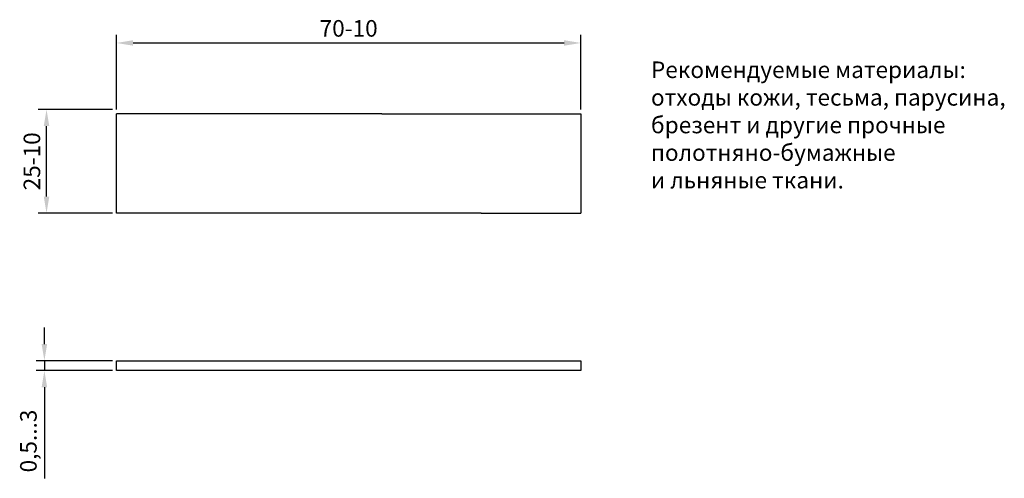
# Model space of a CAD drawing. Units: millimetres. Extents: x -73 to 75, y 113 to 182.
import ezdxf

# ---------------------------------------------------------------- set-up
doc = ezdxf.new("R2010")
doc.units = ezdxf.units.MM
doc.header["$LTSCALE"] = 0.2
doc.dimstyles.new('ISO-25', dxfattribs={"dimtxt": 2.5, "dimasz": 2.5, "dimexe": 1.25, "dimexo": 0.625, "dimtad": 1, "dimtxsty": 'Standard', "dimcen": 2.5, "dimadec": 0, "dimazin": 0, "dimtfac": 1, "dimtmove": 0, "dimatfit": 3, "dimfxl": 0, "dimarcsym": 0})

# ---------------------------------------------------------------- blocks, each defined once
blk = doc.blocks.new('*D1')
at = {"color": 0, "lineweight": -2, "ltscale": 0.25}
for p, q in [((-58.5, 168.78), (-58.5, 180.07)), ((11.5, 168.78), (11.5, 180.07)), ((-56, 178.82), (9, 178.82))]:
    blk.add_line(p, q, dxfattribs=at)
at = {"color": 0, "lineweight": 15, "ltscale": 0.25}
for points in [[(-56, 179.24), (-56, 178.41), (-58.5, 178.82)], [(9, 179.24), (9, 178.41), (11.5, 178.82)]]:
    blk.add_solid(points, dxfattribs=at)
at = {"layer": 'Defpoints', "color": 0, "lineweight": 15, "ltscale": 0.25}
for p in [(11.5, 178.82), (-58.5, 168.15), (11.5, 168.15)]:
    blk.add_point(p, dxfattribs=at)
at = {"color": 0, "lineweight": 15, "ltscale": 0.25, "insert": (-23.5, 180.7), "char_height": 2.5, "attachment_point": 5}
blk.add_mtext('70-10', dxfattribs=at)
blk = doc.blocks.new('*D2')
at = {"color": 0, "lineweight": -2, "ltscale": 0.25}
for p, q in [((-59.12, 168.78), (-70.31, 168.78)), ((-69.06, 155.65), (-69.06, 166.28)), ((-59.12, 153.15), (-70.31, 153.15))]:
    blk.add_line(p, q, dxfattribs=at)
at = {"color": 0, "lineweight": 15, "ltscale": 0.25}
for points in [[(-69.48, 166.28), (-68.64, 166.28), (-69.06, 168.78)], [(-69.48, 155.65), (-68.64, 155.65), (-69.06, 153.15)]]:
    blk.add_solid(points, dxfattribs=at)
at = {"layer": 'Defpoints', "color": 0, "lineweight": 15, "ltscale": 0.25}
for p in [(-69.06, 168.78), (-58.5, 168.78), (-58.5, 153.15)]:
    blk.add_point(p, dxfattribs=at)
at = {"color": 0, "lineweight": 15, "ltscale": 0.25, "insert": (-70.94, 160.96), "char_height": 2.5, "attachment_point": 5, "rotation": 90}
blk.add_mtext('25-10', dxfattribs=at)
blk = doc.blocks.new('*D3')
at = {"color": 0, "lineweight": -2, "ltscale": 0.25}
for p, q in [((-69.38, 133.37), (-69.38, 135.87)), ((-59.12, 130.87), (-70.63, 130.87)), ((-69.38, 130.87), (-69.38, 129.37)), ((-59.12, 129.37), (-70.63, 129.37)), ((-69.38, 126.87), (-69.38, 113.12))]:
    blk.add_line(p, q, dxfattribs=at)
at = {"color": 0, "lineweight": 15, "ltscale": 0.25}
for points in [[(-69.8, 133.37), (-68.97, 133.37), (-69.38, 130.87)], [(-69.8, 126.87), (-68.97, 126.87), (-69.38, 129.37)]]:
    blk.add_solid(points, dxfattribs=at)
at = {"layer": 'Defpoints', "color": 0, "lineweight": 15, "ltscale": 0.25}
for p in [(-58.5, 130.87), (-69.38, 129.37), (-58.5, 129.37)]:
    blk.add_point(p, dxfattribs=at)
at = {"color": 0, "lineweight": 15, "ltscale": 0.25, "insert": (-71.47, 118.75), "char_height": 2.5, "attachment_point": 5, "rotation": 90}
blk.add_mtext('0,5...3', dxfattribs=at)

msp = doc.modelspace()

# ---------------------------------------------------------------- linework, layer by layer
at = {"color": 7, "lineweight": 30, "ltscale": 0.25}
for p, q in [((-18.5, 168.152), (-58.5, 168.152)), ((-58.5, 153.152), (-58.5, 168.152)), ((-18.5, 168.152), (-3.5, 168.152)), ((-3.5, 168.152), (11.5, 168.152)), ((11.5, 168.152), (11.5, 153.152)), ((-18.5, 153.152), (-58.5, 153.152)), ((-3.5, 153.152), (-18.5, 153.152)), ((-3.5, 153.152), (11.5, 153.152)), ((-58.5, 130.873), (-3.5, 130.873)), ((-58.5, 129.373), (-58.5, 130.873)), ((-3.5, 130.873), (11.5, 130.873)), ((11.5, 130.873), (11.5, 129.373)), ((-3.5, 129.373), (-58.5, 129.373)), ((11.5, 129.373), (-3.5, 129.373))]:
    msp.add_line(p, q, dxfattribs=at)

# ---------------------------------------------------------------- texts
at = {"color": 7, "lineweight": 15, "ltscale": 0.25}
for s, p in [('Рекомендуемые материалы:', (22.086, 173.53)), ('отходы кожи, тесьма, парусина,', (22.086, 169.364)), ('брезент и другие прочные', (22.086, 165.197)), ('полотняно-бумажные ', (22.086, 161.03)), ('и льняные ткани.', (22.086, 156.864))]:
    msp.add_text(s, height=2.5, dxfattribs=at).set_placement(p)

# ---------------------------------------------------------------- dimensions: what is measured, and where the dimension line sits
at = {"color": 3, "lineweight": 15, "ltscale": 0.25}
dim = msp.add_linear_dim(base=(11.5, 178.822), p1=(-58.5, 168.152), p2=(11.5, 168.152), text='70-10', dimstyle='ISO-25', dxfattribs=at)
dim.commit()
dim.dimension.update_dxf_attribs({"geometry": '*D1', "text_midpoint": (-23.5, 180.697)})
for base, p1, p2, text, picture, middle in [((-69.061, 168.777), (-58.5, 153.152), (-58.5, 168.777), '25-10', '*D2', (-70.936, 160.965)), ((-69.382, 129.373), (-58.5, 130.873), (-58.5, 129.373), '0,5...3', '*D3', (-71.465, 118.748))]:
    dim = msp.add_linear_dim(base=base, p1=p1, p2=p2, angle=90, text=text, dimstyle='ISO-25', dxfattribs=at)
    dim.commit()
    dim.dimension.update_dxf_attribs({"geometry": picture, "text_midpoint": middle})

doc.saveas('drawing.dxf')
